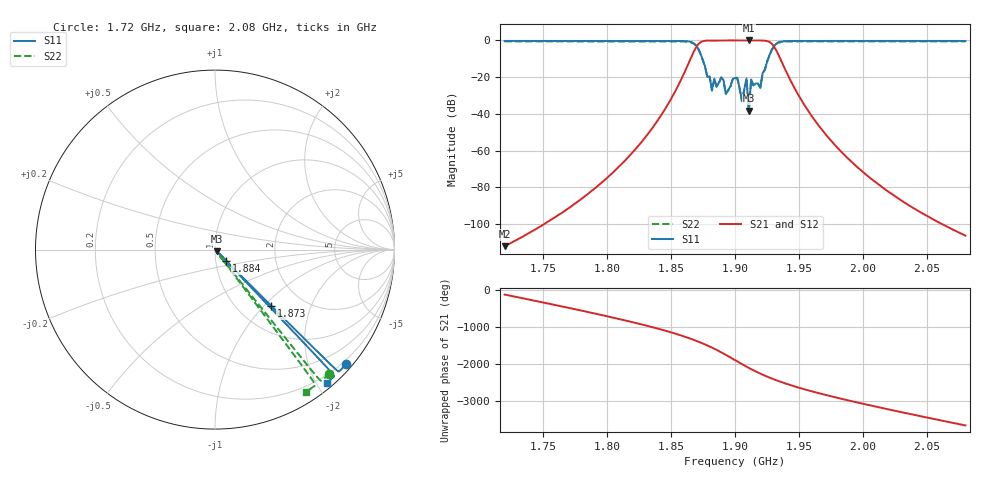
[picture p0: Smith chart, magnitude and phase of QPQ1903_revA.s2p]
! written by passband
# GHZ S DB R 50
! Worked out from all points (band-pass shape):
!   201 points, 1.72 GHz to 2.08 GHz, reference 50 ohm
!   highest |S21| = 0.00 dB at 1.911 GHz (marker M1); lowest = -112.1 dB at 1.72 GHz (marker M2)
!   |S21| within 3 dB of the highest: 1.87 GHz to 1.93 GHz (59.8 MHz wide, 3.15 % of centre)
!   lowest |S11| = -38.3 dB at 1.911 GHz (marker M3), VSWR 1.02, Z = 50.8 - j0.891 ohm
!   |S11| at or under -10 dB: 1.875 GHz to 1.926 GHz (51.31 MHz wide, 2.7 % of centre)
!   |S22| runs from -38.5 to -0.5 dB; largest |S21 - S12| = 0
!   S11 on the Smith chart (normalised r, x): 1.72 GHz: 0.12, -2.65; 1.873 GHz: 1.41, -1.11; 1.884 GHz: 1.13, -0.15; 2.08 GHz: 0.09, -2.14
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1.72  -0.27 -41.3  -112.05 -130.4  -112.05 -130.4  -0.53 -47.3
1.7812  -0.27 -42.8  -85.69 147.4  -85.69 147.4  -0.53 -49.0
1.8406  -0.27 -44.2  -42.53 21.5  -42.53 21.5  -0.53 -50.6
1.864  -0.55 -44.8  -11.96 133.3  -11.96 133.3  -0.82 -51.3
1.873  -7.03 -45.0  -1.03 15.3  -1.03 15.3  -7.30 -51.5
1.8784  -19.77 -45.1  -0.05 -64.8  -0.05 -64.8  -20.04 -51.7
1.8838  -20.86 -45.3  -0.04 -153.0  -0.04 -153.0  -21.13 -51.8
1.8874  -23.11 -45.3  -0.02 143.6  -0.02 143.6  -23.37 -51.9
1.891  -21.60 -45.4  -0.03 76.8  -0.03 76.8  -21.86 -52.0
1.8946  -26.97 -45.5  -0.01 7.1  -0.01 7.1  -27.24 -52.1
1.9  -20.41 -45.6  -0.04 -100.6  -0.04 -100.6  -20.67 -52.3
1.9054  -32.91 -45.8  -0.00 152.0  -0.00 152.0  -33.17 -52.4
1.909  -20.72 -45.9  -0.04 82.6  -0.04 82.6  -20.99 -52.5
1.9108  -38.28 -45.9  -0.00 49.0  -0.00 49.0  -38.54 -52.6
1.9126  -21.25 -45.9  -0.03 16.2  -0.03 16.2  -21.51 -52.6
1.918  -23.46 -46.1  -0.02 -76.8  -0.02 -76.8  -23.72 -52.8
1.9234  -15.71 -46.2  -0.13 -161.5  -0.13 -161.5  -15.97 -52.9
1.9288  -4.97 -46.3  -1.80 121.6  -1.80 121.6  -5.23 -53.1
1.9342  -0.99 -46.5  -8.16 51.4  -8.16 51.4  -1.25 -53.2
1.9612  -0.27 -47.1  -42.44 125.6  -42.44 125.6  -0.53 -53.9
2.0206  -0.27 -48.5  -82.75 4.0  -82.75 4.0  -0.53 -55.6
2.08  -0.27 -50.0  -106.30 -64.6  -106.30 -64.6  -0.53 -57.2
